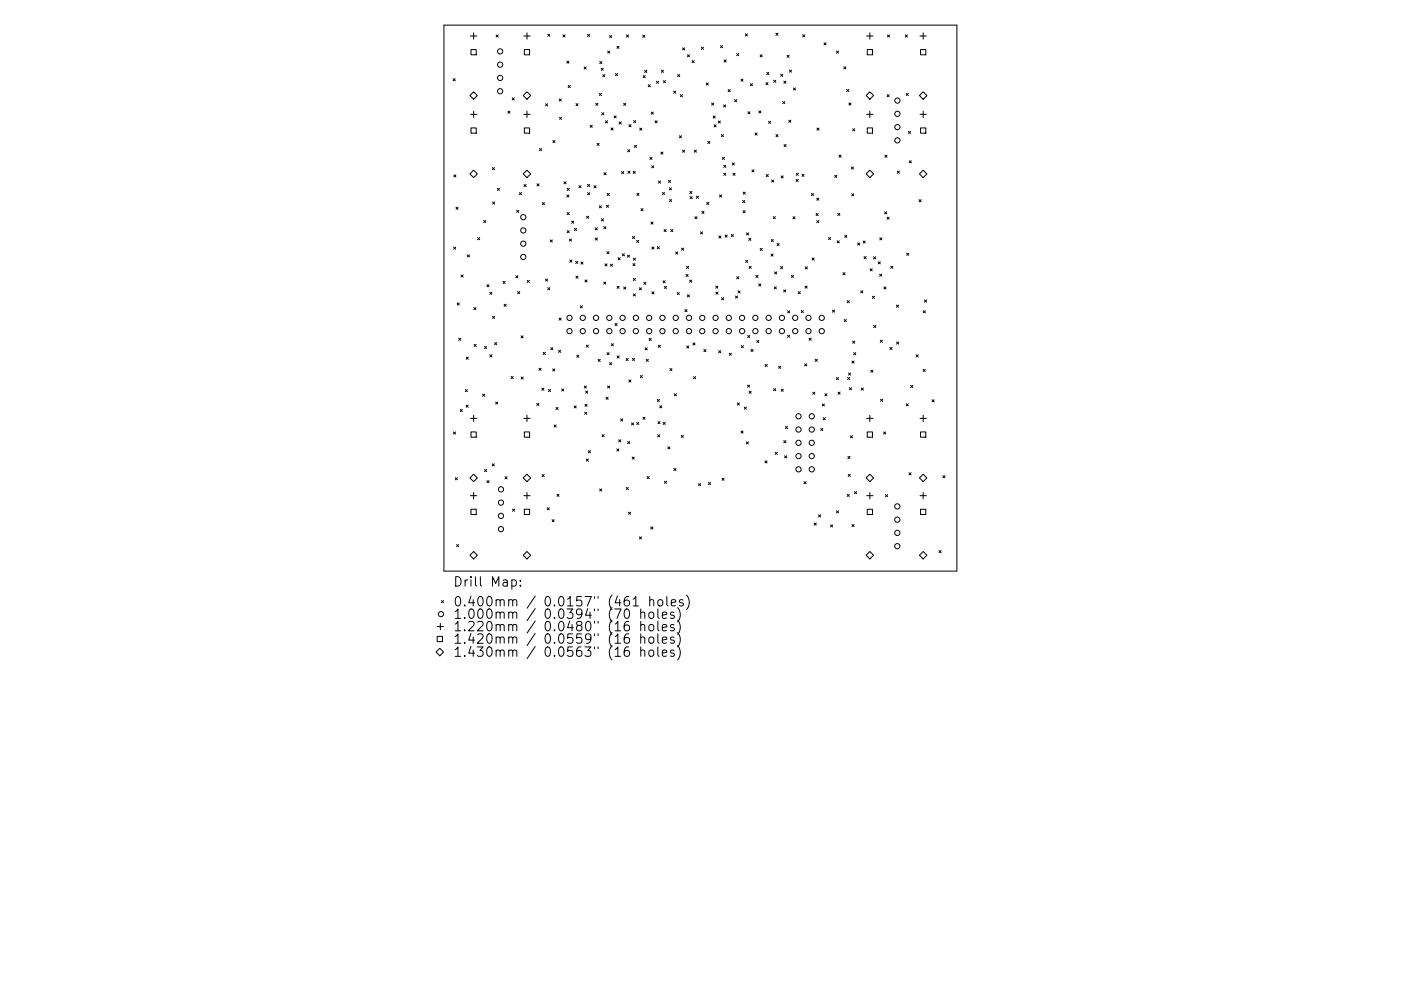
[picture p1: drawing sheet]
<svg xmlns="http://www.w3.org/2000/svg" width="297mm" height="210mm" viewBox="0 0 297 210" stroke-linecap="round" stroke-linejoin="round" font-family="sans-serif">
<defs><g id="words">
<g font-size="2.8">
<text x="96" y="124.5">Drill Map:</text>
<text x="96" y="128.7">0.400mm / 0.0157&quot; (461 holes)</text>
<text x="96" y="131.3">1.000mm / 0.0394&quot; (70 holes)</text>
<text x="96" y="133.9">1.220mm / 0.0480&quot; (16 holes)</text>
<text x="96" y="136.6">1.420mm / 0.0559&quot; (16 holes)</text>
<text x="96" y="139.3">1.430mm / 0.0563&quot; (16 holes)</text>
</g>
</g></defs>
<g fill="none" stroke="#000" stroke-width=".21">
<path d="M94.1 5.3h108.8v115.9h-108.8zM96.1 16.7l.4 .4M96.5 16.7l-.4 .4M99.7 7.6h1.4M99.9 10.5h1.1v1.1h-1.1zM100.4 19.5l.8 .8-.8 .8-.8-.8zM100.4 7v1.3M105.2 7.4l.4 .5M105.6 7.4l-.4 .5M111 7.6h1.4M111.2 10.5h1.1v1.1h-1.1zM111.7 19.5l.8 .8-.8 .8-.8-.8z"/>
<path d="M111.7 7v1.3M116.1 7.2l.5 .5M116.6 7.2l-.5 .5M119.4 7.4l.4 .4M119.8 7.4l-.4 .4M120.2 13l.4 .4M120.5 18.1l.4 .5M120.6 13l-.4 .4M120.9 18.1l-.4 .5M123.8 14.2l.5 .5M124.3 14.2l-.5 .5M124.6 7.3l.4 .4"/>
<path d="M125 7.3l-.4 .4M127.1 19.8l.4 .5M127.2 13.1l.4 .4M127.5 14.5l.4 .4M127.5 19.8l-.4 .5M127.6 13.1l-.4 .4M127.8 15.8l.4 .5M127.9 14.5l-.4 .4M128.2 15.8l-.4 .5M128.8 10.8l.5 .5M129.2 7.5l.5 .5M129.3 10.8l-.5 .5"/>
<path d="M129.7 7.5l-.5 .5M130.5 15.6l.4 .5M130.8 9.8l.5 .5M130.9 15.6l-.4 .5M131.3 9.8l-.5 .5M132.8 7.4l.5 .5M133.3 7.4l-.5 .5M136.3 7.5l.4 .4M136.4 16l.4 .5M136.7 14.9l.4 .5M136.7 7.5l-.4 .4M136.8 16l-.4 .5"/>
<path d="M137.1 14.9l-.4 .5M137.4 18l.5 .4M137.9 18l-.5 .4M139.2 17.2l.4 .5M139.6 17.2l-.4 .5M140.2 14.9l.5 .5M140.7 14.9l-.5 .5M140.7 17.1l.4 .5M141.1 17.1l-.4 .5M142.8 19.3l.5 .5M143.3 19.3l-.5 .5M143.7 15.8l.4 .5"/>
<path d="M144.1 15.8l-.4 .5M144.7 10.2l.5 .4M145.2 10.2l-.5 .4M145.7 11.6l.5 .5M146.2 11.6l-.5 .5M146.7 12.9l.5 .4M147.2 12.9l-.5 .4M148.7 10l.4 .5M149.1 10l-.4 .5M149.7 17.6l.5 .5M150.2 17.6l-.5 .5M152.8 9.7l.4 .4"/>
<path d="M153.2 9.7l-.4 .4M153.5 12.7l.5 .5M154 12.7l-.5 .5M154.4 19l.4 .5M154.8 19l-.4 .5M156.2 11.4l.4 .4M156.6 11.4l-.4 .4M157.1 16.8l.4 .4M157.5 16.8l-.4 .4M158 7.2l.5 .4M158.5 7.2l-.5 .4M159.1 17.7l.4 .5"/>
<path d="M159.5 17.7l-.4 .5M161.2 11.6l.4 .5M161.6 11.6l-.4 .5M162.4 17.5l.4 .5M162.6 15.4l.4 .4M162.8 17.5l-.4 .5M163 15.4l-.4 .4M164 17l.5 .5M164.5 17l-.5 .5M164.5 7l.5 .5M165 7l-.5 .5M165.5 15.8l.5 .4"/>
<path d="M166 15.8l-.5 .4M166.2 17.2l.4 .5M166.6 17.2l-.4 .5M166.9 11.7l.4 .5M167.3 11.7l-.4 .5M167.4 14.9l.4 .4M167.8 14.9l-.4 .4M168.2 18.7l.5 .4M168.7 18.7l-.5 .4M170.2 7.4l.4 .4M170.6 7.4l-.4 .4M174.7 9.1l.4 .4"/>
<path d="M175.1 9.1l-.4 .4M177.3 10.8l.5 .5M177.8 10.8l-.5 .5M178.9 14.2l.5 .4M179.4 14.2l-.5 .4M179.5 19l.5 .4M180 19l-.5 .4M183.8 7.6h1.3M183.9 10.5h1.1v1.1h-1.1zM184.4 19.5l.8 .8-.8 .8-.8-.8zM184.4 7v1.3M188.2 7.4l.4 .5"/>
<path d="M188.6 7.4l-.4 .5M191.9 7.4l.5 .5M192.1 19.8l.5 .5M192.4 7.4l-.5 .5M192.6 19.8l-.5 .5M195.1 7.6h1.3M195.2 10.5h1.1v1.1h-1.1zM195.7 19.5l.8 .8-.8 .8-.8-.8zM195.7 7v1.3M96.2 37.1l.5 .4M96.7 37.1l-.5 .4M99.6 36.9l.8-.8 .8 .8-.8 .8z"/>
<path d="M99.7 24.3h1.4M99.9 27.1h1.1v1.2h-1.1zM100.4 23.6v1.3M104.4 35.6l.4 .4M104.8 35.6l-.4 .4M105.4 40l.5 .4M105.9 40l-.5 .4M107.7 23.6l.4 .4M108.1 23.6l-.4 .4M108.6 20.7l.4 .5M109 20.7l-.4 .5M110.9 36.9l.8-.8 .8 .8-.8 .8z"/>
<path d="M111 24.3h1.4M111.1 39.1l.4 .5M111.2 27.1h1.1v1.2h-1.1zM111.5 39.1l-.4 .5M111.7 23.6v1.3M113.9 39l.4 .4M114.3 39l-.4 .4M114.4 31.5l.4 .5M114.8 31.5l-.4 .5M115.7 22l.4 .5M116.1 22l-.4 .5M117.2 29.8l.5 .5"/>
<path d="M117.7 29.8l-.5 .5M118.6 21l.4 .4M118.6 24.9l.5 .4M119 21l-.4 .4M119.1 24.9l-.5 .4M119.6 38.6l.4 .4M120 38.6l-.4 .4M120.3 40l.4 .4M120.7 40l-.4 .4M122.1 22l.5 .4M122.6 22l-.5 .4M122.7 39.4l.5 .4"/>
<path d="M123.2 39.4l-.5 .4M124.6 39.1l.4 .5M125 39.1l-.4 .5M125.1 26.6l.5 .4M125.6 26.6l-.5 .4M125.9 39.4l.5 .5M126.3 21.9l.5 .5M126.4 39.4l-.5 .5M126.6 30.4l.4 .5M126.8 21.9l-.5 .5M127 30.4l-.4 .5M127.6 23.9l.4 .5"/>
<path d="M128 23.9l-.4 .5M128.1 36.6l.4 .5M128.4 25.6l.4 .5M128.5 36.6l-.4 .5M128.8 25.6l-.4 .5M129.5 27.1l.5 .5M130 27.1l-.5 .5M130.2 24.6l.4 .4M130.6 24.6l-.4 .4M131.3 25.9l.4 .4M131.7 25.9l-.4 .4M131.8 36.4l.4 .4"/>
<path d="M132.2 21.9l.5 .5M132.2 36.4l-.4 .4M132.7 21.9l-.5 .5M133.1 31.8l.4 .4M133.1 36.3l.5 .5M133.3 26.5l.5 .4M133.5 31.8l-.4 .4M133.6 36.3l-.5 .5M133.8 26.5l-.5 .4M134.2 36.3l.5 .5M134.3 25.6l.5 .4M134.5 30.8l.5 .5"/>
<path d="M134.7 36.3l-.5 .5M134.8 25.6l-.5 .4M135 30.8l-.5 .5M135.6 27.2l.5 .4M136.1 27.2l-.5 .4M137.8 33.4l.4 .4M138.1 23.8l.4 .4M138.2 35.2l.4 .4M138.2 33.4l-.4 .4M138.5 23.8l-.4 .4M138.6 35.2l-.4 .4M138.9 25.6l.4 .5"/>
<path d="M139.3 25.6l-.4 .5M139.6 38.4l.5 .5M140.1 38.4l-.5 .5M140.1 32.3l.5 .4M140.6 32.3l-.5 .4M141.7 38.3l.5 .4M141.9 39.9l.5 .4M142.2 38.3l-.5 .4M142.4 39.9l-.5 .4M144.1 28.8l.4 .4M144.3 20.1l.4 .4M144.5 28.8l-.4 .4"/>
<path d="M144.7 20.1l-.4 .4M144.7 31.9l.5 .4M145.2 31.9l-.5 .4M147.2 31.9l.5 .4M147.7 31.9l-.5 .4M150.1 30l.4 .4M150.5 30l-.4 .4M150.9 21.9l.4 .4M151.2 24.6l.4 .5M151.3 21.9l-.4 .4M151.4 26.5l.4 .4M151.6 24.6l-.4 .5"/>
<path d="M151.8 26.5l-.4 .4M152.3 25.7l.4 .4M152.7 25.7l-.4 .4M152.9 28.6l.5 .4M153.2 33.4l.4 .4M153.4 28.6l-.5 .4M153.4 22.3l.4 .4M153.4 35.1l.5 .4M153.4 36.8l.5 .4M153.6 33.4l-.4 .4M153.8 22.3l-.4 .4M153.9 35.1l-.5 .4"/>
<path d="M153.9 36.8l-.5 .4M155.3 34.6l.4 .4M155.4 36.8l.5 .4M155.7 34.6l-.4 .4M155.8 21.1l.4 .5M155.9 36.8l-.5 .4M156.2 21.1l-.4 .5M158.6 23.7l.4 .5M159 23.7l-.4 .5M159.4 36l.5 .5M159.9 36l-.5 .5M160.1 28.2l.4 .5"/>
<path d="M160.5 28.2l-.4 .5M160.9 23.5l.4 .5M161.3 23.5l-.4 .5M162.5 37l.4 .5M162.9 37l-.4 .5M162.9 25.7l.5 .5M163.4 25.7l-.5 .5M163.6 38.2l.4 .4M164 38.2l-.4 .4M164.5 28.6l.5 .4M165 28.6l-.5 .4M165.6 37.3l.5 .5"/>
<path d="M165.9 21.5l.5 .5M166.1 37.3l-.5 .5M166.2 30.7l.5 .4M166.4 21.5l-.5 .5M166.7 30.7l-.5 .4M167.2 25.5l.5 .4M167.7 25.5l-.5 .4M168.8 38.1l.4 .4M168.8 36.8l.5 .4M169.2 38.1l-.4 .4M169.3 36.8l-.5 .4M170 37l.5 .4"/>
<path d="M170.5 37l-.5 .4M173.2 27.2l.5 .4M173.7 27.2l-.5 .4M177 37.2l.4 .4M177.4 37.2l-.4 .4M177.9 32.9l.4 .4M178.3 32.9l-.4 .4M180 21.8l.4 .5M180.4 21.8l-.4 .5M180.5 35.4l.5 .5M180.8 27.3l.4 .5M181 35.4l-.5 .5"/>
<path d="M181.2 27.3l-.4 .5M183.8 24.3h1.3M183.9 27.1h1.1v1.2h-1.1zM184.4 36.1l.8 .8-.8 .8-.8-.8zM184.4 23.6v1.3M187.6 32.9l.5 .5M188.1 32.9l-.5 .5M188.1 20.1l.4 .4M188.5 20.1l-.4 .4M190.3 36.3l.4 .5M190.7 36.3l-.4 .5M192.6 27.9l.4 .4"/>
<path d="M192.8 34.1l.4 .5M193 27.9l-.4 .4M193.2 34.1l-.4 .5M195.1 24.3h1.3M195.2 27.1h1.1v1.2h-1.1zM195.7 36.1l.8 .8-.8 .8-.8-.8zM195.7 23.6v1.3M96.2 52.4l.4 .5M96.6 52.4l-.4 .5M96.7 44l.4 .4M97.1 44l-.4 .4M97.7 58.3l.5 .5"/>
<path d="M98.2 58.3l-.5 .5M99.1 54.1l.4 .4M99.5 54.1l-.4 .4M101.3 50.4l.4 .5M101.7 50.4l-.4 .5M102.5 46.8l.5 .4M103 46.8l-.5 .4M104.4 42.9l.5 .4M104.9 42.9l-.5 .4M106.7 59.7l.4 .4M107.1 59.7l-.4 .4M109.4 58.5l.4 .5"/>
<path d="M109.5 44.6l.5 .5M109.8 58.5l-.4 .5M110 44.6l-.5 .5M110.1 40.9l.5 .4M110.6 40.9l-.5 .4M111.8 59.5l.4 .4M112.2 59.5l-.4 .4M115 43l.4 .4M115.4 43l-.4 .4M115.7 59.2l.4 .4M116.1 59.2l-.4 .4M116.7 50.9l.4 .4"/>
<path d="M117.1 50.9l-.4 .4M120.2 41.4l.4 .4M120.2 45.1l.5 .4M120.2 48.9l.5 .5M120.6 41.4l-.4 .4M120.7 45.1l-.5 .4M120.7 48.9l-.5 .5M120.7 50.7l.5 .4M120.8 55.2l.5 .4M121.2 50.7l-.5 .4M121.2 46.9l.4 .5M121.3 55.2l-.5 .4"/>
<path d="M121.6 46.9l-.4 .5M121.8 48.5l.4 .4M122.1 55.5l.4 .4M122.1 58.6l.5 .4M122.2 48.5l-.4 .4M122.5 55.5l-.4 .4M122.6 58.6l-.5 .4M123.2 55.6l.4 .4M123.6 55.6l-.4 .4M124 59.4l.5 .4M124.4 45.9l.4 .4M124.5 59.4l-.5 .4"/>
<path d="M124.6 40.9l.4 .4M124.8 45.9l-.4 .4M125 40.9l-.4 .4M126.2 48.3l.4 .5M126.2 50.5l.5 .4M126.6 48.3l-.4 .5M126.7 50.5l-.5 .4M127.1 43.7l.4 .4M127.5 43.7l-.4 .4M127.5 46.4l.5 .5M128 46.4l-.5 .5M128 59.8l.4 .5"/>
<path d="M128 48.1l.5 .4M128.3 56l.4 .4M128.4 59.8l-.4 .5M128.5 48.1l-.5 .4M128.6 43.5l.4 .5M128.7 53.4l.4 .4M128.7 56l-.4 .4M128.8 41l.4 .5M129 43.5l-.4 .5M129.1 53.4l-.4 .4M129.2 41l-.4 .5M129.4 56l.5 .5"/>
<path d="M129.9 56l-.5 .5M131 54.7l.5 .4M131.5 54.7l-.5 .4M132 53.8l.4 .5M132.4 53.8l-.4 .5M133 54.1l.5 .5M133.5 54.1l-.5 .5M134.1 50.2l.4 .4M134.2 55.9l.4 .5M134.3 59.1l.4 .4M134.3 54.8l.4 .4M134.5 50.2l-.4 .4"/>
<path d="M134.6 55.9l-.4 .5M134.7 59.1l-.4 .4M134.7 54.8l-.4 .4M135 51l.4 .4M135 41l.5 .5M135.4 51l-.4 .4M135.5 41l-.5 .5M135.9 44.3l.4 .4M136.3 44.3l-.4 .4M136.5 59.9l.4 .4M136.9 59.9l-.4 .4M138 47.1l.5 .4"/>
<path d="M138.2 52.4l.5 .4M138.5 47.1l-.5 .4M138.7 52.4l-.5 .4M139.4 52.3l.4 .5M139.8 52.3l-.4 .5M140.4 40.8l.5 .5M140.6 59.6l.4 .4M140.8 48.7l.4 .4M140.9 40.8l-.5 .5M141 59.6l-.4 .4M141.2 48.7l-.4 .4M142 42.3l.4 .5"/>
<path d="M142.2 48.7l.5 .4M142.4 42.3l-.4 .5M142.7 48.7l-.5 .4M143.3 53.5l.4 .4M143.7 53.5l-.4 .4M144.5 52.6l.4 .5M144.9 52.6l-.4 .5M145.4 58.2l.5 .5M145.6 56.5l.4 .4M145.9 58.2l-.5 .5M146 56.5l-.4 .4M146.2 59.4l.5 .5"/>
<path d="M146.3 40.6l.4 .5M146.3 41.7l.5 .5M146.7 59.4l-.5 .5M146.7 40.6l-.4 .5M146.8 41.7l-.5 .5M147.3 46l.5 .4M147.6 41.6l.5 .5M147.8 46l-.5 .4M148.1 41.6l-.5 .5M148.5 49.2l.5 .4M148.8 44.8l.4 .5M149 49.2l-.5 .4"/>
<path d="M149.2 44.8l-.4 .5M149.8 42.9l.5 .5M150.3 42.9l-.5 .5M152.4 50.1l.5 .4M152.6 41.4l.4 .4M152.9 50.1l-.5 .4M153 41.4l-.4 .4M153.7 49.9l.5 .4M154.2 49.9l-.5 .4M155.1 49.8l.4 .4M155.5 49.8l-.4 .4M156.2 58.7l.4 .4"/>
<path d="M156.6 58.7l-.4 .4M157.5 42.5l.4 .5M157.6 44.7l.4 .4M157.6 40.8l.4 .4M157.9 42.5l-.4 .5M158 44.7l-.4 .4M158 40.8l-.4 .4M158.1 55.2l.4 .5M158.3 49.4l.4 .5M158.5 55.2l-.4 .5M158.7 49.4l-.4 .5M158.8 50.6l.4 .4"/>
<path d="M158.8 56.5l.5 .5M159.2 50.6l-.4 .4M159.3 56.5l-.5 .5M160.3 58.4l.4 .5M160.7 58.4l-.4 .5M161.2 52.7l.4 .4M161.6 52.7l-.4 .4M163.5 53.9l.4 .4M163.5 50.8l.5 .4M163.9 53.9l-.4 .4M163.9 46l.5 .4M164 50.8l-.5 .4"/>
<path d="M164.2 57.7l.5 .4M164.4 46l-.5 .4M164.7 57.7l-.5 .4M164.8 51.7l.4 .4M165.2 51.7l-.4 .4M165.5 56.6l.4 .4M165.9 56.6l-.4 .4M167.8 58.4l.4 .5M168.1 46l.5 .4M168.2 58.4l-.4 .5M168.6 46l-.5 .4M170.7 56.6l.5 .5"/>
<path d="M171.2 56.6l-.5 .5M172 41.1l.5 .4M172.2 54.7l.4 .5M172.5 41.1l-.5 .4M172.6 54.7l-.4 .5M173 45.3l.5 .4M173.2 42l.4 .5M173.2 46.8l.4 .4M173.5 45.3l-.5 .4M173.6 42l-.4 .5M173.6 46.8l-.4 .4M175.7 50.4l.4 .4"/>
<path d="M176.1 50.4l-.4 .4M177.5 51.1l.4 .4M177.6 45.3l.5 .4M177.9 51.1l-.4 .4M178.1 45.3l-.5 .4M178.7 57.9l.5 .4M179.1 49.9l.4 .5M179.2 57.9l-.5 .4M179.5 49.9l-.4 .5M180.6 41.1l.4 .5M181 41.1l-.4 .5M181.8 51.5l.5 .5"/>
<path d="M182.3 51.5l-.5 .5M183 51.1l.4 .5M183.2 54.4l.4 .5M183.4 51.1l-.4 .5M183.6 54.4l-.4 .5M184.5 57l.4 .5M184.9 57l-.4 .5M185.2 54.5l.5 .4M185.7 54.5l-.5 .4M186.2 55.5l.4 .5M186.5 58.2l.4 .4M186.5 50.4l.5 .5"/>
<path d="M186.6 55.5l-.4 .5M186.9 58.2l-.4 .4M187 50.4l-.5 .5M187.6 44.9l.4 .5M188 44.9l-.4 .5M188.1 46.1l.4 .4M188.5 46.1l-.4 .4M188.9 56.5l.4 .4M189.3 56.5l-.4 .4M192.2 53.7l.5 .5M192.7 53.7l-.5 .5M194.9 42.4l.4 .4"/>
<path d="M195.3 42.4l-.4 .4M96.9 64.3l.5 .4M97.2 71.8l.5 .4M97.4 64.3l-.5 .4M97.7 71.8l-.5 .4M98.8 75.8l.5 .4M99.3 75.8l-.5 .4M100.5 65.3l.4 .4M100.5 73.1l.5 .4M100.9 65.3l-.4 .4M101 73.1l-.5 .4M102.7 73.5l.5 .5"/>
<path d="M103.2 73.5l-.5 .5M103.2 60.4l.5 .4M103.7 60.4l-.5 .4M103.8 62l.5 .5M103.9 75.3l.4 .4M104.3 62l-.5 .5M104.3 75.3l-.4 .4M104.4 67.1l.5 .5M104.9 67.1l-.5 .5M104.9 72.7l.4 .4M105.3 72.7l-.4 .4M106.9 64.6l.4 .4"/>
<path d="M107.3 64.6l-.4 .4M108.4 79.9l.4 .4M108.8 79.9l-.4 .4M109.8 61.9l.4 .4M110.2 61.9l-.4 .4M110.5 71.3l.4 .4M110.5 80l.4 .4M110.9 71.3l-.4 .4M110.9 80l-.4 .4M114.3 78.1l.4 .5M114.7 78.1l-.4 .5M115.2 74.8l.4 .4"/>
<path d="M115.6 74.8l-.4 .4M116.1 61l.5 .5M116.6 61l-.5 .5M116.8 73.8l.4 .4M117.2 78.3l.4 .4M117.2 73.8l-.4 .4M117.6 78.3l-.4 .4M118.4 74.3l.5 .5M118.5 67.5l.5 .4M118.9 74.3l-.5 .5M119 67.5l-.5 .4M122.3 75.4l.4 .4"/>
<path d="M122.7 75.4l-.4 .4M123 64.9l.5 .4M123.5 64.9l-.5 .4M124.3 73.2l.4 .5M124.7 73.2l-.4 .5M126.8 76.2l.5 .5M127.3 76.2l-.5 .5M128.7 74.8l.4 .5M129.1 74.8l-.4 .5M129.2 76.9l.5 .5M129.6 72.9l.5 .5M129.7 76.9l-.5 .5"/>
<path d="M130.1 72.9l-.5 .5M130.4 68.6l.4 .5M130.8 60.7l.5 .5M130.8 68.6l-.4 .5M130.8 75.5l.5 .5M131.3 60.7l-.5 .5M131.3 75.5l-.5 .5M132.2 60.9l.5 .4M132.7 60.9l-.5 .4M132.7 76.1l.5 .4M133.2 76.1l-.5 .4M134.1 76l.4 .5"/>
<path d="M134.3 62.4l.4 .4M134.5 76l-.4 .5M134.7 62.4l-.4 .4M135.6 61.1l.4 .4M135.8 79.7l.4 .4M136 61.1l-.4 .4M136.2 79.7l-.4 .4M136.8 73.8l.4 .4M137 76.2l.5 .5M137.2 73.8l-.4 .4M137.5 76.2l-.5 .5M137.6 71.8l.5 .4"/>
<path d="M138.1 71.8l-.5 .4M138.2 61.9l.5 .5M138.7 61.9l-.5 .5M139.6 73.2l.4 .5M140 73.2l-.4 .5M140.9 60.8l.4 .4M141.3 60.8l-.4 .4M142 78.2l.5 .4M142.5 78.2l-.5 .4M143.6 62.1l.4 .4M144 62.1l-.4 .4M145.2 65.7l.5 .4"/>
<path d="M145.6 73.4l.4 .4M145.7 65.7l-.5 .4M145.7 62.6l.5 .4M146 73.4l-.4 .4M146.2 62.6l-.5 .4M146.9 72.7l.5 .5M147 79.9l.5 .5M147.4 72.7l-.5 .5M147.5 79.9l-.5 .5M149.2 74.2l.5 .4M149.7 74.2l-.5 .4M151.8 60.7l.4 .4"/>
<path d="M151.8 62l.4 .4M152.2 60.7l-.4 .4M152.2 62l-.4 .4M152.4 74.4l.4 .5M152.8 74.4l-.4 .5M153 63.2l.4 .4M153.4 63.2l-.4 .4M154.6 74.9l.5 .5M155.1 74.9l-.5 .5M155.9 62.8l.5 .5M156.4 62.8l-.5 .5M156.5 61.7l.4 .5"/>
<path d="M156.9 61.7l-.4 .5M157.2 73.3l.4 .5M157.6 73.3l-.4 .5M158.5 71.2l.5 .4M159 71.2l-.5 .4M159.2 74.1l.5 .5M159.7 74.1l-.5 .5M160.5 72.2l.4 .5M160.9 60.2l.4 .5M160.9 72.2l-.4 .5M161.3 60.2l-.4 .5M162.2 77.3l.5 .5"/>
<path d="M162.7 77.3l-.5 .5M164.2 60.8l.4 .5M164.6 60.8l-.4 .5M165.1 77.7l.4 .5M165.5 77.7l-.4 .5M166.2 61.5l.4 .4M166.6 61.5l-.4 .4M167 71.1l.4 .5M167 65.9l.4 .5M167.4 71.1l-.4 .5M167.4 65.9l-.4 .5M169.2 61.9l.5 .4"/>
<path d="M169.7 61.9l-.5 .4M169.9 65.9l.4 .4M170.3 65.9l-.4 .4M170.6 77.2l.4 .4M170.7 60.7l.4 .4M171 77.2l-.4 .4M171.1 60.7l-.4 .4M171.5 71.7l.5 .5M172 71.7l-.5 .5M172.8 76.2l.5 .5M173.3 76.2l-.5 .5M176.5 65.8l.4 .4"/>
<path d="M176.9 65.8l-.4 .4M179 67.8l.4 .4M179.4 67.8l-.4 .4M179.6 63.8l.5 .4M179.9 79.1l.4 .5M180.1 63.8l-.5 .4M180.3 79.1l-.4 .5M180.6 76.6l.5 .4M180.8 72.4l.4 .4M181 74.8l.4 .5M181.1 76.6l-.5 .4M181.2 72.4l-.4 .4"/>
<path d="M181.4 74.8l-.4 .5M182.5 61.7l.4 .4M182.9 61.7l-.4 .4M184.6 78.5l.5 .5M185 62.9l.4 .4M185.1 78.5l-.5 .5M185.2 69l.5 .5M185.4 62.9l-.4 .4M185.7 69l-.5 .5M186.6 72.2l.5 .4M187.1 72.2l-.5 .4M187.4 60.9l.5 .4"/>
<path d="M187.9 60.9l-.5 .4M188.7 73.7l.4 .5M189.1 73.7l-.4 .5M190.1 64.7l.4 .5M190.1 72.6l.4 .4M190.5 64.7l-.4 .5M190.5 72.6l-.4 .4M194.2 75.3l.5 .4M194.7 75.3l-.5 .4M195.7 78.4l.5 .4M195.8 65.9l.4 .5M196 63.7l.5 .4"/>
<path d="M196.2 78.4l-.5 .4M196.2 65.9l-.4 .5M196.5 63.7l-.5 .4M96.1 91.7l.5 .4M96.6 91.7l-.5 .4M97.6 86.9l.4 .4M98 86.9l-.4 .4M98.7 82.7l.4 .4M98.8 86l.5 .4M99.1 82.7l-.4 .4M99.3 86l-.5 .4M99.7 88.8h1.4"/>
<path d="M99.9 91.6h1.1v1.2h-1.1zM100.4 88.1v1.3M102.3 83.6l.5 .5M102.7 99.6l.5 .5M102.8 83.6l-.5 .5M103.2 99.6l-.5 .5M104.4 98.4l.4 .4M104.8 98.4l-.4 .4M105.1 85.3l.4 .4M105.5 85.3l-.4 .4M111 88.8h1.4M111.2 91.6h1.1v1.2h-1.1z"/>
<path d="M111.7 88.1v1.3M113.8 85.6l.4 .4M114.2 85.6l-.4 .4M114.9 82.4l.4 .4M115.3 82.4l-.4 .4M116.3 82.6l.4 .5M116.7 82.6l-.4 .5M117.5 90.2l.4 .4M117.9 86.4l.4 .5M117.9 90.2l-.4 .4M118.3 86.4l-.4 .5M119.1 82.5l.4 .5"/>
<path d="M119.5 82.5l-.4 .5M121.7 86.1l.5 .4M122.2 86.1l-.5 .4M123.9 81.9l.4 .4M124 87.5l.4 .4M124 85.8l.5 .4M124.2 83l.4 .4M124.3 97.4l.5 .4M124.3 81.9l-.4 .4M124.4 87.5l-.4 .4M124.5 85.8l-.5 .4M124.6 83l-.4 .4"/>
<path d="M124.7 95.6l.5 .5M124.8 97.4l-.5 .4M125.2 95.6l-.5 .5M127.6 92.2l.5 .5M128.1 92.2l-.5 .5M128.5 84.3l.4 .4M128.8 81.9l.5 .4M128.9 84.3l-.4 .4M129.3 81.9l-.5 .4M130.8 95.2l.4 .5M131.2 93.3l.4 .5M131.2 95.2l-.4 .5"/>
<path d="M131.6 88.9l.4 .4M131.6 93.3l-.4 .5M132 88.9l-.4 .4M133.1 93.7l.4 .4M133.3 80.6l.5 .4M133.5 93.7l-.4 .4M133.8 80.6l-.5 .4M133.9 89.7l.4 .5M134 97l.5 .4M134.3 89.7l-.4 .5M134.5 97l-.5 .4M135 89.6l.4 .5"/>
<path d="M135.4 89.6l-.4 .5M136.3 88.5l.5 .5M136.8 88.5l-.5 .5M139.4 84.7l.4 .5M139.4 92.2l.5 .5M139.5 89.5l.5 .4M139.8 84.7l-.4 .5M139.9 86.1l.4 .4M139.9 92.2l-.5 .5M140 89.5l-.5 .4M140.3 86.1l-.4 .4M140.6 89.6l.4 .4"/>
<path d="M141 89.6l-.4 .4M141.6 94.8l.4 .4M142 94.8l-.4 .4M142.9 99.4l.4 .4M143 83.5l.4 .5M143.3 99.4l-.4 .4M143.4 83.5l-.4 .5M144.4 92.4l.5 .4M144.9 92.4l-.5 .4M156.3 85.5l.5 .4M156.8 85.5l-.5 .4M157.1 91.4l.5 .5"/>
<path d="M157.6 91.4l-.5 .5M157.8 86.4l.4 .4M158.2 93.8l.5 .4M158.2 86.4l-.4 .4M158.5 81.7l.4 .4M158.7 93.8l-.5 .4M158.8 83l.5 .4M158.9 81.7l-.4 .4M159.3 83l-.5 .4M162.2 97.8l.4 .4M162.6 97.8l-.4 .4M164 82.5l.5 .4"/>
<path d="M164.4 96l.4 .4M164.5 82.5l-.5 .4M164.8 96l-.4 .4M165.6 82.6l.5 .4M166.1 82.6l-.5 .4M166.2 93.5l.4 .4M166.3 96.7l.5 .5M166.5 90.5l.5 .4M166.6 93.5l-.4 .4M166.8 96.7l-.5 .5M167 90.5l-.5 .4M172.3 83.2l.5 .5"/>
<path d="M172.8 83.2l-.5 .5M174 90.9l.5 .4M174.4 85.7l.4 .4M174.5 90.9l-.5 .4M174.6 88.6l.4 .5M174.8 85.7l-.4 .4M174.9 83.5l.4 .5M175 88.6l-.4 .5M175.3 83.5l-.4 .5M177.3 80.1l.5 .4M177.7 83.2l.4 .4M177.8 80.1l-.5 .4"/>
<path d="M178.1 83.2l-.4 .4M179.7 80.1l.5 .4M179.8 96.8l.4 .5M180.1 82.3l.4 .4M180.2 80.1l-.5 .4M180.2 96.8l-.4 .5M180.3 92.5l.4 .4M180.5 82.3l-.4 .4M180.7 92.5l-.4 .4M182.6 82.3l.5 .5M183.1 82.3l-.5 .5M183.8 88.8h1.3"/>
<path d="M183.9 91.6h1.1v1.2h-1.1zM184.4 88.1v1.3M186.7 84.7l.4 .5M187.1 84.7l-.4 .5M187.3 91.6l.5 .5M187.8 91.6l-.5 .5M192.1 85.7l.5 .4M192.6 85.7l-.5 .4M193.1 81.8l.4 .4M193.5 81.8l-.4 .4M195.1 88.8h1.3M195.2 91.6h1.1v1.2h-1.1z"/>
<path d="M195.7 88.1v1.3M197.6 84.8l.5 .5M198.1 84.8l-.5 .5M96.5 101.4l.5 .4M96.8 115.5l.4 .5M97 101.4l-.5 .4M97.2 115.5l-.4 .5M99.6 101.4l.8-.8 .8 .8-.8 .8zM99.6 117.8l.8-.8 .8 .8-.8 .8zM99.7 105.2h1.4M99.9 108h1.1v1.2h-1.1zM100.4 104.5v1.3"/>
<path d="M103.2 102l.5 .4M103.7 102l-.5 .4M107.1 101.2l.4 .4M107.5 101.2l-.4 .4M108.7 108l.4 .5M109.1 108l-.4 .5M110.9 101.4l.8-.8 .8 .8-.8 .8zM110.9 117.8l.8-.8 .8 .8-.8 .8zM111 105.2h1.4M111.2 108h1.1v1.2h-1.1zM111.7 104.5v1.3M114.9 100.7l.5 .4"/>
<path d="M115.4 100.7l-.5 .4M116 107.7l.5 .5M116.5 107.7l-.5 .5M117.1 110.3l.4 .4M117.5 110.3l-.4 .4M118.1 104.9l.4 .4M118.5 104.9l-.4 .4M127.1 103.7l.5 .5M127.6 103.7l-.5 .5M132.8 103.4l.4 .5M133.2 103.4l-.4 .5M133.3 108.7l.4 .4"/>
<path d="M133.7 108.7l-.4 .4M135.6 113.9l.4 .4M136 113.9l-.4 .4M137.2 101.1l.4 .4M137.6 101.1l-.4 .4M138 111.8l.4 .4M138.4 111.8l-.4 .4M140.9 102.1l.4 .4M141.3 102.1l-.4 .4M148.1 102.6l.4 .4M148.5 102.6l-.4 .4M150.2 102.4l.5 .4"/>
<path d="M150.7 102.4l-.5 .4M153.1 101.5l.4 .4M153.5 101.5l-.4 .4M170.5 102.2l.4 .4M170.9 102.2l-.4 .4M172.6 111l.5 .4M173.1 111l-.5 .4M173.6 109.2l.4 .5M174 109.2l-.4 .5M176.1 111.4l.4 .4M176.5 111.4l-.4 .4M177.3 108.4l.5 .4"/>
<path d="M177.8 108.4l-.5 .4M179.6 104.9l.5 .4M179.8 100.6l.5 .5M180.1 104.9l-.5 .4M180.3 100.6l-.5 .5M180.6 111.3l.5 .4M181.1 111.3l-.5 .4M181.2 104.3l.4 .5M181.6 104.3l-.4 .5M183.8 105.2h1.3M183.9 108h1.1v1.2h-1.1zM184.4 100.6l.8 .8-.8 .8-.8-.8z"/>
<path d="M184.4 117l.8 .8-.8 .8-.8-.8zM184.4 104.5v1.3M187.7 104.9l.5 .5M188.2 104.9l-.5 .5M192.7 100.3l.5 .5M193.2 100.3l-.5 .5M195.1 105.2h1.3M195.2 108h1.1v1.2h-1.1zM195.7 100.6l.8 .8-.8 .8-.8-.8zM195.7 117l.8 .8-.8 .8-.8-.8zM195.7 104.5v1.3M199.1 116.8l.4 .5"/>
<path d="M199.5 116.8l-.4 .5M199.9 100.9l.5 .5M200.4 100.9l-.5 .5M92.5 138.3l.7-.7 .8 .7-.8 .8zM92.7 132.9h1.3M92.7 135h1.1v1.1h-1.1zM93.4 132.3v1.3M93.6 127.4l.4 .5M94 127.4l-.4 .5M108.5 123.1l.6-.1 .4 .4v.6l-.2 .3h-.8M110.3 124.2v.2M110.3 123.1v.2"/>
<path d="M132.5 129.4l.5-.2a1.25 1.25 0 0 1 0 2l-.4-.1-.2-.3-.1-.8zM133.3 131.8a.79 .79 0 0 0-1 .9v.8l.2 .2 .6 .1 .3-.2 .1-.6-.2-.3-.6-.1-.4 .4M133.3 134.5a.79 .79 0 0 0-1 .8v.8l.2 .3 .6 .1 .3-.2 .1-.7-.2-.3-.6-.1-.4 .4M133.3 137.3a.79 .79 0 0 0-1 .8v.8l.2 .3 .6 .1 .3-.2 .1-.7-.2-.3-.6-.1-.4 .4M134.2 128.6h1.2M135.9 130.1a.5 .5 0 0 1 .8 0v1.1M135.9 132.7a.5 .5 0 0 1 .8 .1v1M135.9 135.3a.5 .5 0 0 1 .8 .1v1.1M135.9 138.1a.5 .5 0 0 1 .8 .1v1.1M135.9 129.2v2M135.9 131.8v2M135.9 134.5v2"/>
<path d="M135.9 137.3v2M137.7 130.1a.54 .54 0 0 1 .5-.2 .54 .54 0 0 1 .4 .3v.6a.54 .54 0 0 1-.5 .4 .54 .54 0 0 1-.5-.4zM137.7 132.7a.54 .54 0 0 1 .5-.2 .54 .54 0 0 1 .4 .4v.6a.54 .54 0 0 1-.5 .4 .54 .54 0 0 1-.5-.4zM137.7 135.3a.54 .54 0 0 1 .5-.2 .54 .54 0 0 1 .4 .4v.6a.54 .54 0 0 1-.5 .4 .54 .54 0 0 1-.5-.4zM137.7 138.1a.54 .54 0 0 1 .5-.2 .54 .54 0 0 1 .4 .4v.6a.54 .54 0 0 1-.5 .4 .54 .54 0 0 1-.5-.4zM137.8 127.4l.2-.2 .5 .1 .1 1.3M137.8 126.6v2M139.5 129.2v1.7l.3 .3M139.5 131.8v1.8l.3 .2M139.5 134.5v1.7l.3 .3M139.5 137.3v1.7l.3 .3M139.7 127.3l.2-.1a.54 .54 0 0 1 .6 .4v.6a.54 .54 0 0 1-.5 .4 .54 .54 0 0 1-.5-.4v-.6z"/>
<path d="M140.4 130.5l1-.2-.1-.3-.6-.1-.3 .2 .1 1h.8M140.4 133.2l1-.2-.1-.4-.6-.1-.3 .3 .1 .9h.8M140.4 135.8l1-.2-.1-.4-.6-.1-.3 .3 .1 1h.8M140.4 138.6l1-.2-.1-.4-.6-.1-.3 .3 .1 1h.8M141.4 126.6v1.7l.3 .3M142.3 127.9l1-.2-.1-.4-.6-.1-.3 .3 .1 1h.8M142.9 130l-.5-.1-.3 .2 .1 .3 .7 .2v.5h-.8M142.9 132.6l-.5-.1-.3 .3 .1 .3 .7 .2v.4h-.8M142.9 135.2l-.5-.1-.3 .3 .1 .3 .7 .2v.5h-.8M142.9 138l-.5-.1-.3 .3 .1 .3 .7 .2v.5h-.8M143.7 128.9a2.29 2.29 0 0 1 0 3.1M143.7 131.6a2.29 2.29 0 0 1 0 3"/>
<path d="M143.7 134.2a2.29 2.29 0 0 1 0 3M143.7 137a2.29 2.29 0 0 1 0 3M144.8 127.3l-.5-.1-.3 .3 .1 .3 .7 .2v.5h-.8M145.6 126.3a2.29 2.29 0 0 1 0 3"/>
<circle cx="106" cy="19.4" r=".55"/>
<circle cx="106" cy="16.5" r=".55"/>
<circle cx="106" cy="13.7" r=".55"/>
<circle cx="106" cy="10.9" r=".55"/>
<circle cx="190.3" cy="24.2" r=".55"/>
<circle cx="190.3" cy="29.8" r=".55"/>
<circle cx="190.3" cy="27" r=".55"/>
<circle cx="190.3" cy="21.3" r=".55"/>
<circle cx="110.9" cy="46.1" r=".55"/>
<circle cx="110.9" cy="48.9" r=".55"/>
<circle cx="110.9" cy="54.5" r=".55"/>
<circle cx="110.9" cy="51.7" r=".55"/>
<circle cx="120.7" cy="67.4" r=".55"/>
<circle cx="120.7" cy="70.3" r=".55"/>
<circle cx="123.6" cy="67.4" r=".55"/>
<circle cx="123.6" cy="70.3" r=".55"/>
<circle cx="126.4" cy="67.4" r=".55"/>
<circle cx="126.4" cy="70.3" r=".55"/>
<circle cx="129.2" cy="67.4" r=".55"/>
<circle cx="129.2" cy="70.3" r=".55"/>
<circle cx="132" cy="67.4" r=".55"/>
<circle cx="132" cy="70.3" r=".55"/>
<circle cx="134.8" cy="67.4" r=".55"/>
<circle cx="134.8" cy="70.3" r=".55"/>
<circle cx="137.6" cy="67.4" r=".55"/>
<circle cx="137.6" cy="70.3" r=".55"/>
<circle cx="140.4" cy="67.4" r=".55"/>
<circle cx="140.4" cy="70.3" r=".55"/>
<circle cx="143.3" cy="67.4" r=".55"/>
<circle cx="143.3" cy="70.3" r=".55"/>
<circle cx="146.1" cy="67.4" r=".55"/>
<circle cx="146.1" cy="70.3" r=".55"/>
<circle cx="148.9" cy="67.4" r=".55"/>
<circle cx="148.9" cy="70.3" r=".55"/>
<circle cx="151.7" cy="67.4" r=".55"/>
<circle cx="151.7" cy="70.3" r=".55"/>
<circle cx="154.5" cy="67.4" r=".55"/>
<circle cx="154.5" cy="70.3" r=".55"/>
<circle cx="157.3" cy="67.4" r=".55"/>
<circle cx="157.3" cy="70.3" r=".55"/>
<circle cx="160.2" cy="67.4" r=".55"/>
<circle cx="160.2" cy="70.3" r=".55"/>
<circle cx="163" cy="67.4" r=".55"/>
<circle cx="163" cy="70.3" r=".55"/>
<circle cx="165.8" cy="67.4" r=".55"/>
<circle cx="165.8" cy="70.3" r=".55"/>
<circle cx="168.6" cy="67.4" r=".55"/>
<circle cx="168.6" cy="70.3" r=".55"/>
<circle cx="171.4" cy="67.4" r=".55"/>
<circle cx="171.4" cy="70.3" r=".55"/>
<circle cx="174.2" cy="67.4" r=".55"/>
<circle cx="174.2" cy="70.3" r=".55"/>
<circle cx="169.3" cy="88.3" r=".55"/>
<circle cx="169.3" cy="91.1" r=".55"/>
<circle cx="169.3" cy="94" r=".55"/>
<circle cx="169.3" cy="99.6" r=".55"/>
<circle cx="169.3" cy="96.8" r=".55"/>
<circle cx="172.1" cy="88.3" r=".55"/>
<circle cx="172.1" cy="91.1" r=".55"/>
<circle cx="172.1" cy="94" r=".55"/>
<circle cx="172.1" cy="99.6" r=".55"/>
<circle cx="172.1" cy="96.8" r=".55"/>
<circle cx="106.2" cy="106.6" r=".55"/>
<circle cx="106.2" cy="103.8" r=".55"/>
<circle cx="106.2" cy="109.5" r=".55"/>
<circle cx="106.2" cy="112.3" r=".55"/>
<circle cx="190.2" cy="115.9" r=".55"/>
<circle cx="190.2" cy="113.1" r=".55"/>
<circle cx="190.2" cy="110.3" r=".55"/>
<circle cx="190.2" cy="107.4" r=".55"/>
<circle cx="93.5" cy="130.3" r=".55"/>
</g>
<use href="#words"/>
</svg>
